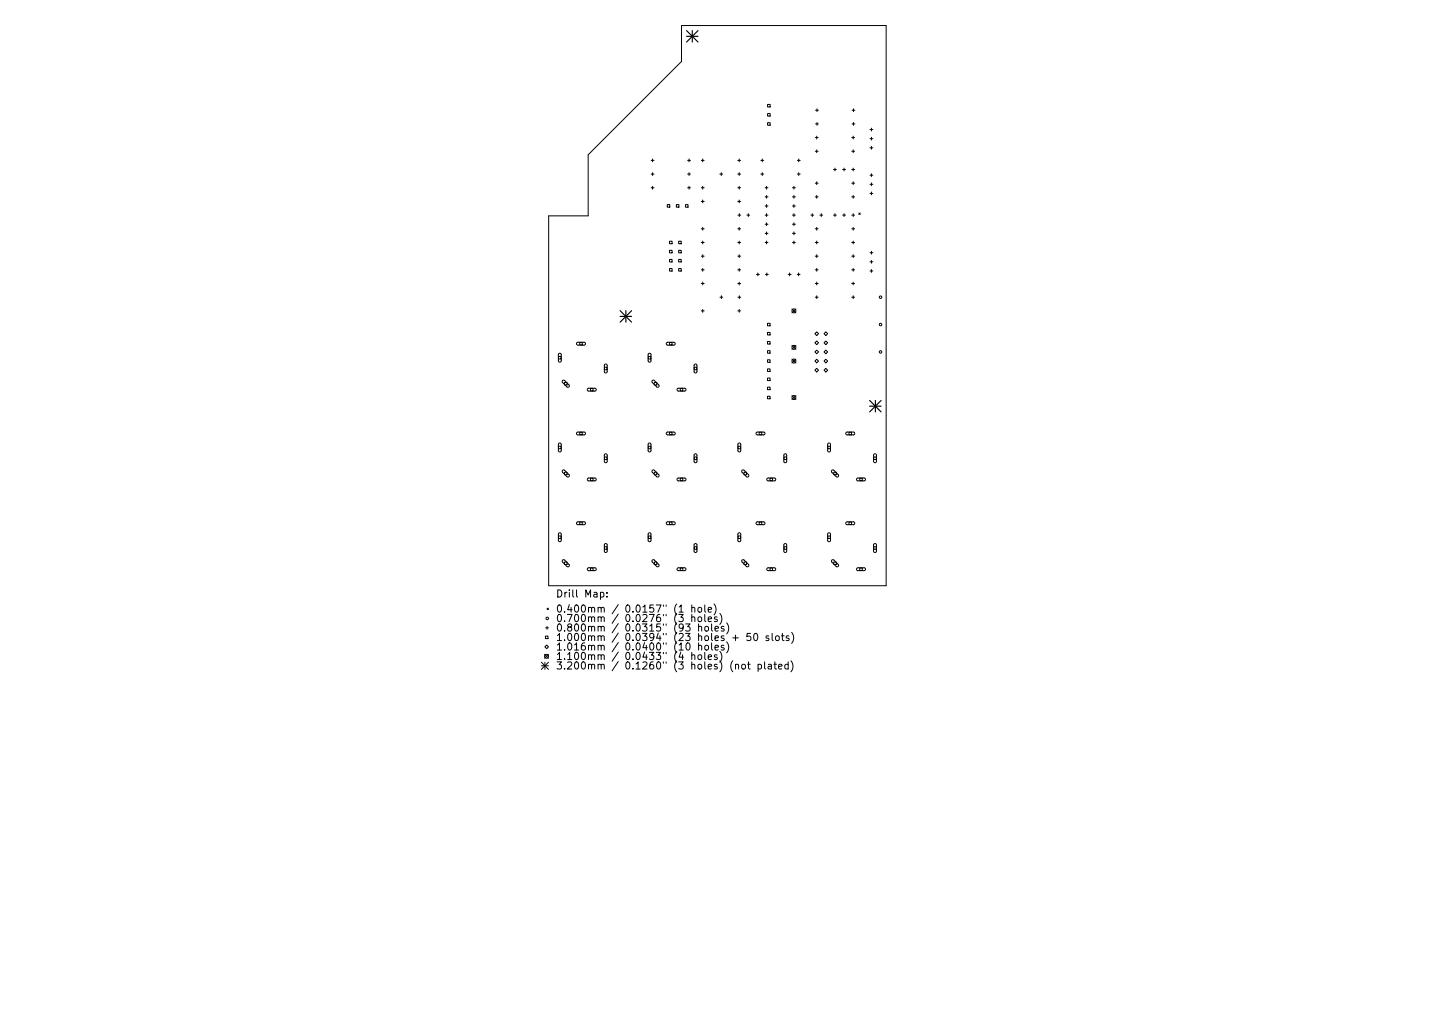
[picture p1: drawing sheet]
<svg xmlns="http://www.w3.org/2000/svg" width="297mm" height="210mm" viewBox="0 0 297 210" stroke-linecap="round" stroke-linejoin="round" font-family="sans-serif">
<defs><g id="words">
<g font-size="2.1">
<text x="115" y="123.6">Drill Map:</text>
<text x="115" y="126.8">0.400mm / 0.0157&quot; (1 hole)</text>
<text x="115" y="128.7">0.700mm / 0.0276&quot; (3 holes)</text>
<text x="115" y="130.7">0.800mm / 0.0315&quot; (93 holes)</text>
<text x="115" y="132.6">1.000mm / 0.0394&quot; (23 holes + 50 slots)</text>
<text x="115" y="134.6">1.016mm / 0.0400&quot; (10 holes)</text>
<text x="115" y="136.6">1.100mm / 0.0433&quot; (4 holes)</text>
<text x="115" y="138.5">3.200mm / 0.1260&quot; (3 holes) (not plated)</text>
</g>
</g></defs>
<g fill="none" stroke="#000" stroke-width=".21">
<path d="M141.1 5.3h42.3v115.9h-69.8v-76.5h8.1v-12.7l19.4-19.3zM134.8 33.2h.6M134.8 36h.6M134.8 38.9h.6M135.1 32.9v.6M135.1 35.7v.6M135.1 38.6v.6M142.3 33.2h.6M142.3 36h.6M142.3 38.9h.6M142.6 32.9v.6M142.6 35.7v.6"/>
<path d="M142.6 38.6v.6M145.2 33.2h.6M145.2 38.9h.6M145.5 32.9v.6M145.5 38.6v.6M149 36h.6M149.3 35.7v.6M152.7 33.2h.6M152.7 36h.6M152.7 38.9h.6M153 32.9v.6M153 35.7v.6"/>
<path d="M153 38.6v.6M157.5 33.2h.6M157.5 36h.6M157.8 32.9v.6M157.8 35.7v.6M158.4 38.9h.6M158.7 38.6v.6M158.9 21.6h.5v.5h-.5zM158.9 23.5h.5v.5h-.5zM158.9 25.4h.5v.5h-.5zM164 38.9h.6M164.3 38.6v.6"/>
<path d="M165 33.2h.6M165 36h.6M165.3 32.9v.6M165.3 35.7v.6M168.8 28.5h.6M168.8 31.3h.6M168.8 37.9h.6M168.8 22.8h.6M168.8 25.6h.6M169.1 28.2v.6M169.1 31v.6M169.1 37.6v.6"/>
<path d="M169.1 22.5v.6M169.1 25.3v.6M172.5 35.1h.6M172.8 34.8v.6M174.4 35.1h.6M174.7 34.8v.6M176.3 28.5h.6M176.3 31.3h.6M176.3 37.9h.6M176.3 35.1h.6M176.4 22.8h.6M176.4 25.6h.6"/>
<path d="M176.6 28.2v.6M176.6 31v.6M176.6 34.8v.6M176.6 37.6v.6M176.7 22.5v.6M176.7 25.3v.6M180.1 26.8h.6M180.1 28.7h.6M180.1 30.6h.6M180.1 36.3h.6M180.1 38.1h.6M180.4 26.5v.6"/>
<path d="M180.4 28.4v.6M180.4 30.3v.6M180.4 36v.5M180.4 37.8v.6M180.4 39.7v.6M138.1 42.3h.5v.6h-.5zM138.6 49.9h.5v.5h-.5zM138.6 51.8h.5v.5h-.5zM138.6 53.7h.5v.5h-.5zM138.6 55.6h.5v.5h-.5zM140 42.3h.5v.6h-.5zM140.5 49.9h.5v.5h-.5z"/>
<path d="M140.5 51.8h.5v.5h-.5zM140.5 53.7h.5v.5h-.5zM140.5 55.6h.5v.5h-.5zM141.9 42.3h.5v.6h-.5zM145.2 41.7h.6M145.2 47.3h.6M145.2 50.2h.6M145.2 53h.6M145.2 55.8h.6M145.2 58.7h.6M145.5 41.4v.6M145.5 47.1v.5"/>
<path d="M145.5 49.9v.6M145.5 52.7v.6M145.5 55.5v.6M145.5 58.4v.6M152.7 41.7h.6M152.7 47.3h.6M152.7 50.2h.6M152.7 53h.6M152.7 55.8h.6M152.7 58.7h.6M152.7 44.5h.6M153 41.4v.6"/>
<path d="M153 47.1v.5M153 49.9v.6M153 52.7v.6M153 55.5v.6M153 58.4v.6M153 44.2v.6M154.6 44.5h.6M154.9 44.2v.6M156.6 56.8h.6M156.9 56.5v.6M158.4 50.2h.6M158.4 44.5h.6"/>
<path d="M158.4 40.7h.6M158.4 42.6h.6M158.4 46.4h.6M158.4 48.3h.6M158.4 56.8h.6M158.7 40.4v.6M158.7 42.3v.6M158.7 44.2v.6M158.7 46.1v.6M158.7 48v.6M158.7 49.9v.6M158.7 56.5v.6"/>
<path d="M163.2 56.8h.6M163.5 56.5v.6M164 50.2h.6M164 44.5h.6M164 40.7h.6M164 42.6h.6M164 46.4h.6M164 48.3h.6M164.3 40.4v.6M164.3 42.3v.6M164.3 44.2v.6M164.3 46.1v.6"/>
<path d="M164.3 48v.6M164.3 49.9v.6M165 56.8h.6M165.3 56.5v.6M167.8 44.5h.6M168.1 44.2v.6M168.8 47.3h.6M168.8 50.2h.6M168.8 53h.6M168.8 55.8h.6M168.8 58.7h.6M168.8 40.7h.6"/>
<path d="M169.1 40.4v.6M169.1 47.1v.5M169.1 49.9v.6M169.1 52.7v.6M169.1 55.5v.6M169.1 58.4v.6M169.7 44.5h.6M170 44.2v.6M172.5 44.5h.6M172.8 44.2v.6M174.4 44.5h.6M174.7 44.2v.6"/>
<path d="M176.3 47.3h.6M176.3 50.2h.6M176.3 53h.6M176.3 55.8h.6M176.3 58.7h.6M176.3 44.5h.6M176.3 40.7h.6M176.6 40.4v.6M176.6 44.2v.6M176.6 47.1v.5M176.6 49.9v.6M176.6 52.7v.6"/>
<path d="M176.6 55.5v.6M176.6 58.4v.6M177.8 44.1l.3 .3M178.1 44.1l-.3 .3M180.1 40h.6M180.1 52.3h.6M180.1 54.2h.6M180.1 56.1h.6M180.4 52v.6M180.4 53.9v.6M180.4 55.8v.6M115.6 73.8h.5v.5h-.5z"/>
<path d="M115.7 73.2l.3-.1 .2 .2v1.4l-.3 .3-.3-.3zM116.5 78.7h.4l.9 1v.4h-.5l-.9-1zM116.8 79.1h.6v.6h-.6zM119.4 70.9l1.5-.1 .3 .4-.3 .2h-1.3l-.2-.2zM120 70.9h.5v.5h-.5zM125.1 76h.6v.5h-.6zM125.2 75.4l.3-.1 .2 .3v1.3l-.3 .3-.3-.3zM134.2 73.8h.5v.5h-.5zM134.2 73.2l.4-.1 .1 .2v1.4l-.2 .3-.3-.3zM135 78.7h.5l.9 1-.1 .4h-.4l-.9-1zM135.4 79.1h.6v.6h-.6zM138 70.9l1.5-.1 .3 .4-.3 .2h-1.3l-.3-.2z"/>
<path d="M138.6 70.9h.5v.5h-.5zM143.7 76h.5v.5h-.5zM143.8 75.4l.2-.1 .3 .3v1.3l-.3 .3-.3-.3zM145.2 64.3h.6M145.5 64v.6M149 61.5h.6M149.3 61.2v.6M152.7 64.3h.6M152.7 61.5h.6M153 64v.6M153 61.2v.6M158.9 66.9h.5v.5h-.5z"/>
<path d="M158.9 68.8h.5v.5h-.5zM158.9 70.7h.5v.5h-.5zM158.9 72.6h.5v.5h-.5zM158.9 74.5h.5v.5h-.5zM158.9 76.3h.5v.6h-.5zM158.9 78.2h.5v.6h-.5zM163.9 63.9l.8 .8M163.9 71.5l.8 .8M163.9 74.3l.8 .8M164.7 63.9l-.8 .8M164.7 71.5l-.8 .8M164.7 74.3l-.8 .8"/>
<path d="M168.7 69.1l.4-.4 .3 .4-.3 .3zM168.7 70.9l.4-.3 .3 .3-.3 .4zM168.7 74.7l.4-.4 .3 .4-.3 .4zM168.7 76.6l.4-.4 .3 .4-.3 .4zM168.8 61.5h.6M169.1 72.5l.3 .3-.3 .4-.4-.4zM169.1 61.2v.6M170.6 69.1l.3-.4 .4 .4-.4 .3zM170.6 70.9l.3-.3 .4 .3-.4 .4zM170.6 72.8l.3-.3 .4 .3-.4 .4zM170.6 74.7l.3-.4 .4 .4-.4 .4zM170.6 76.6l.3-.4 .4 .4-.4 .4z"/>
<path d="M176.3 61.5h.6M176.6 61.2v.6M115.6 92.3h.5v.6h-.5zM115.7 91.8l.3-.1 .2 .2v1.4l-.3 .2-.3-.2zM116.5 97.3h.4l.9 1v.3h-.5l-.9-.9zM116.8 97.7h.6v.5h-.6zM119.4 89.5l1.5-.1 .3 .4-.3 .2h-1.3l-.2-.2zM120 89.4h.5v.6h-.5zM121.6 80.4l1.6-.1 .2 .4-.2 .2h-1.4l-.2-.2zM121.6 99l1.6-.1 .2 .4-.2 .2h-1.4l-.2-.2zM122.2 80.4h.6v.5h-.6zM122.2 99h.6v.5h-.6z"/>
<path d="M125.1 94.6h.6v.5h-.6zM125.2 94l.3-.1 .2 .3v1.3l-.3 .3-.3-.3zM134.2 92.3h.5v.6h-.5zM134.2 91.8l.4-.1 .1 .2v1.4l-.2 .2-.3-.2zM135 97.3h.5l.9 1-.1 .3-.3 .1-1-1zM135.4 97.7h.6v.5h-.6zM138 89.5l1.5-.1 .3 .4-.3 .2h-1.3l-.3-.2zM138.6 89.4h.5v.6h-.5zM140.2 80.4l1.6-.1 .2 .4-.2 .2h-1.4l-.2-.2zM140.2 99l1.6-.1 .2 .4-.2 .2h-1.4l-.2-.2zM140.8 80.4h.5v.5h-.5zM140.8 99h.5v.5h-.5z"/>
<path d="M143.7 94.6h.5v.5h-.5zM143.8 94l.3-.1 .2 .3v1.3l-.3 .3-.3-.3zM152.8 92.3h.5v.6h-.5zM152.8 91.8l.3-.1 .2 .2v1.4l-.2 .2-.4-.2zM153.6 97.3h.4l1 1-.1 .3-.4 .1-.9-1zM154 97.7h.5v.5h-.5zM156.6 89.5l1.5-.1 .2 .4-.2 .2h-1.4l-.2-.2zM157.2 89.4h.5v.6h-.5zM158.8 99l1.5-.1 .3 .4-.3 .2h-1.3l-.3-.2zM158.9 80.1h.5v.5h-.5zM158.9 82h.5v.5h-.5zM159.4 99h.5v.5h-.5z"/>
<path d="M162.3 94.6h.5v.5h-.5zM162.3 94l.3-.1 .2 .3v1.3l-.2 .3-.3-.3zM163.9 81.9l.8 .8M164.7 81.9l-.8 .8M171.3 92.3h.6v.6h-.6zM171.4 91.8l.3-.1 .2 .2v1.4l-.2 .2-.4-.2zM172.2 97.3h.4l.9 1v.3h-.4l-.9-.9zM172.6 97.7h.5v.5h-.5zM175.2 89.5l1.5-.1 .2 .4-.2 .2h-1.4l-.2-.2zM175.7 89.4h.6v.6h-.6zM177.4 99l1.5-.1 .3 .4-.3 .2h-1.4l-.2-.2zM178 99h.5v.5h-.5z"/>
<path d="M180.9 94.6h.5v.5h-.5zM180.9 94l.3-.1 .2 .3v1.3l-.2 .3-.4-.3zM115.6 110.9h.5v.5h-.5zM115.7 110.3h.3l.2 .2v1.4l-.3 .2-.3-.2zM116.5 115.9h.4l.9 .9v.4h-.5l-.9-.9zM116.8 116.3h.6v.5h-.6zM119.4 108.1l1.5-.1 .3 .3-.3 .3h-1.3l-.2-.2zM120 108h.5v.5h-.5zM121.6 117.6l1.6-.1 .2 .3-.2 .3h-1.4l-.2-.2zM122.2 117.5h.6v.6h-.6zM125.1 113.1h.6v.6h-.6zM125.2 112.6l.3-.1 .2 .2v1.4l-.3 .2-.3-.2z"/>
<path d="M134.2 110.9h.5v.5h-.5zM134.2 110.3h.4l.1 .2v1.4l-.2 .2-.3-.2zM135 115.9h.4l.9 .9v.4l-.3 .1-1-1zM135.4 116.3h.6v.5h-.6zM138 108.1l1.5-.1 .3 .3-.3 .3h-1.3l-.3-.2zM138.6 108h.5v.5h-.5zM140.2 117.6l1.6-.1 .2 .3-.2 .3h-1.4l-.2-.2zM140.8 117.5h.5v.6h-.5zM143.7 113.1h.5v.6h-.5zM143.8 112.6l.3-.1 .2 .2v1.4l-.3 .2-.3-.2zM152.8 110.9h.5v.5h-.5zM152.8 110.3h.3l.2 .2v1.4l-.2 .2-.4-.2z"/>
<path d="M153.6 115.9h.4l.9 .9v.4l-.4 .1-.9-1zM154 116.3h.5v.5h-.5zM156.6 108.1l1.5-.1 .2 .3-.2 .3h-1.4l-.2-.2zM157.2 108h.5v.5h-.5zM158.8 117.6l1.5-.1 .3 .3-.3 .3h-1.3l-.3-.2zM159.4 117.5h.5v.6h-.5zM162.3 113.1h.5v.6h-.5zM162.3 112.6l.3-.1 .2 .2v1.4l-.2 .2-.3-.2zM171.3 110.9h.6v.5h-.6zM171.4 110.3h.3l.2 .2v1.4l-.2 .2-.4-.2zM172.2 115.9h.4l.9 .9v.4h-.4l-.9-.9zM172.6 116.3h.5v.5h-.5z"/>
<path d="M175.2 108.1l1.5-.1 .2 .3-.2 .3h-1.4l-.2-.2zM175.7 108h.6v.5h-.6zM177.4 117.6l1.5-.1 .3 .3-.3 .3h-1.4l-.2-.2zM178 117.5h.5v.6h-.5zM180.9 113.1h.5v.6h-.5zM180.9 112.6l.3-.1 .2 .2v1.4l-.2 .2-.4-.2zM112 137l1.5 1.5M112 137.8h1.5M112.7 135.4l.8 .8M112.8 133.9l.4-.4 .3 .4-.3 .3zM112.8 137v1.5M112.9 131.6h.5v.6h-.5z"/>
<path d="M112.9 129.9h.6M113.2 125.9l.3 .3M113.2 129.6v.6M113.5 125.9l-.3 .3M113.5 135.4l-.8 .8M113.5 137l-1.5 1.5M124.3 122.6h.4l.3 .3-.1 .6h-.6M125.6 123.4v.2M125.6 122.6v.2M140.6 125.6l.4-.4v1.5M141.9 129.1h.9l-.5 .6 .5 .1v.7l-.2 .1-.7-.1M142.2 133.1l.1-.1a.79 .79 0 0 1 .6 .8 .79 .79 0 0 1-.6 .7 .99 .99 0 0 1-.1-1.4z"/>
<path d="M143.2 125.8l.2-.1 .4 .1v.9M143.2 127.8l.2-.1h.4v.9M143.2 135.6l.2-.1 .4 .1v.9M143.2 125.2v1.5M143.2 127.2v1.4M143.2 135v1.5M144.5 127.8l.3-.1 .4 .1v.6l-.1 .2h-.3l-.3-.1zM144.5 135.6l.3-.1 .4 .1v.6l-.1 .2-.3 .1-.3-.2zM144.6 125.8l.4-.1 .2 .3v.4l-.2 .3-.4-.1-.1-.2zM144.6 129.8l.2-.2 .4 .1v.9M144.6 133.7l.2-.2 .4 .1v.9M144.6 129.1v1.5"/>
<path d="M144.6 133v1.5M145.9 125.2v1.3l.2 .2M145.9 127.2v1.2l.2 .2M145.9 135v1.3l.2 .2M146 129.7l.4-.1 .3 .3v.4l-.3 .3-.4-.1-.1-.2zM146 133.6l.4-.1 .3 .3v.4l-.3 .3h-.4l-.1-.3zM146.6 126.2l.7-.2-.1-.2-.4-.1-.2 .2 .1 .7h.5M146.6 128.1l.7-.1-.1-.3h-.4l-.2 .2 .1 .7h.5M146.6 136l.7-.1-.1-.3-.4-.1-.2 .2 .1 .7h.5M147.3 129.1v1.3l.2 .2M147.3 133v1.3l.2 .2M147.8 125a1.7 1.7 0 0 1 0 2.2"/>
<path d="M148 130.1l.7-.1-.1-.3-.4-.1-.2 .2 .1 .7h.5M148 134l.7-.1-.1-.3-.4-.1-.2 .2 .1 .8h.5M148.4 127.7h-.3l-.2 .2v.2l.5 .1v.4h-.5M148.4 135.6l-.3-.1-.2 .2v.2l.5 .2v.3h-.5M149 126.9a1.7 1.7 0 0 1 0 2.3M149 134.8a1.7 1.7 0 0 1 0 2.3M149.8 129.7l-.3-.1-.2 .2 .1 .2 .4 .2v.3h-.5M149.8 133.6l-.3-.1-.2 .2 .1 .3 .4 .1v.4h-.5M150.4 128.9a1.7 1.7 0 0 1 0 2.3M150.4 132.8a1.7 1.7 0 0 1 0 2.3M151.7 132h1.1M152.3 137.6l.2-.1h.3l.1 1"/>
<path d="M153.7 137.5h.3l.3 .2v.5l-.3 .3-.3-.1-.2-.2zM154.7 137.5h.6M154.9 137v1.2l.4 .3M155.4 131.1h-.7l-.1 .7 .2-.2 .5 .1 .1 .2v.5l-.2 .2-.6-.2M156.1 131.2l.3-.1a.79 .79 0 0 1 .5 .7 .79 .79 0 0 1-.5 .8l-.3-.2-.1-.4zM156.9 137.5h.4l.3 .2-.1 .7h-.6M156.9 137.5v1.5M158.3 137v1.2l.2 .3M159 137.5h.6l.1 1M159.1 131.6h-.3l-.2 .2v.2l.5 .1v.4h-.5M159.7 137.8l-.5 .1-.2 .2 .2 .4 .5-.1M159.8 131.1v1.3l.2 .2"/>
<path d="M160.2 137.5h.5M160.4 137v1.2l.3 .3M160.7 131.6h.3l.3 .3v.4l-.3 .3-.3-.1-.2-.2zM161.2 138l.7-.2-.1-.3h-.4l-.2 .2v.7h.6M161.7 131.6h.6M161.9 131.1v1.3l.4 .2M163.2 137.5h-.5l-.3 .2 .2 .7h.6M163.2 137v1.5M163.3 131.6h-.4l-.2 .2 .1 .2 .5 .1v.4h-.6M163.7 136.8a1.7 1.7 0 0 1 0 2.2M163.9 130.9a1.7 1.7 0 0 1 0 2.2"/>
<circle cx="164.3" cy="74.7" r=".41"/>
<circle cx="164.3" cy="71.9" r=".41"/>
<circle cx="164.3" cy="64.3" r=".41"/>
<circle cx="182.3" cy="61.5" r=".26"/>
<circle cx="182.3" cy="67.2" r=".26"/>
<circle cx="182.3" cy="72.8" r=".26"/>
<circle cx="164.3" cy="82.3" r=".41"/>
<circle cx="113.1" cy="135.8" r=".41"/>
<circle cx="113.3" cy="128" r=".26"/>
</g>
<path d="M142.1 6.3l2.4 2.4M142.1 7.5h2.4M143.3 6.3v2.4M144.5 6.3l-2.4 2.4M128.4 64.3l2.3 2.4M128.4 65.5h2.3M129.6 64.3v2.4M130.7 64.3l-2.3 2.4M180 82.9l2.4 2.3M180 84.1h2.4M181.2 82.9v2.3M182.4 82.9l-2.4 2.3" fill="none" stroke="#000" stroke-width=".24"/>
<use href="#words"/>
</svg>
